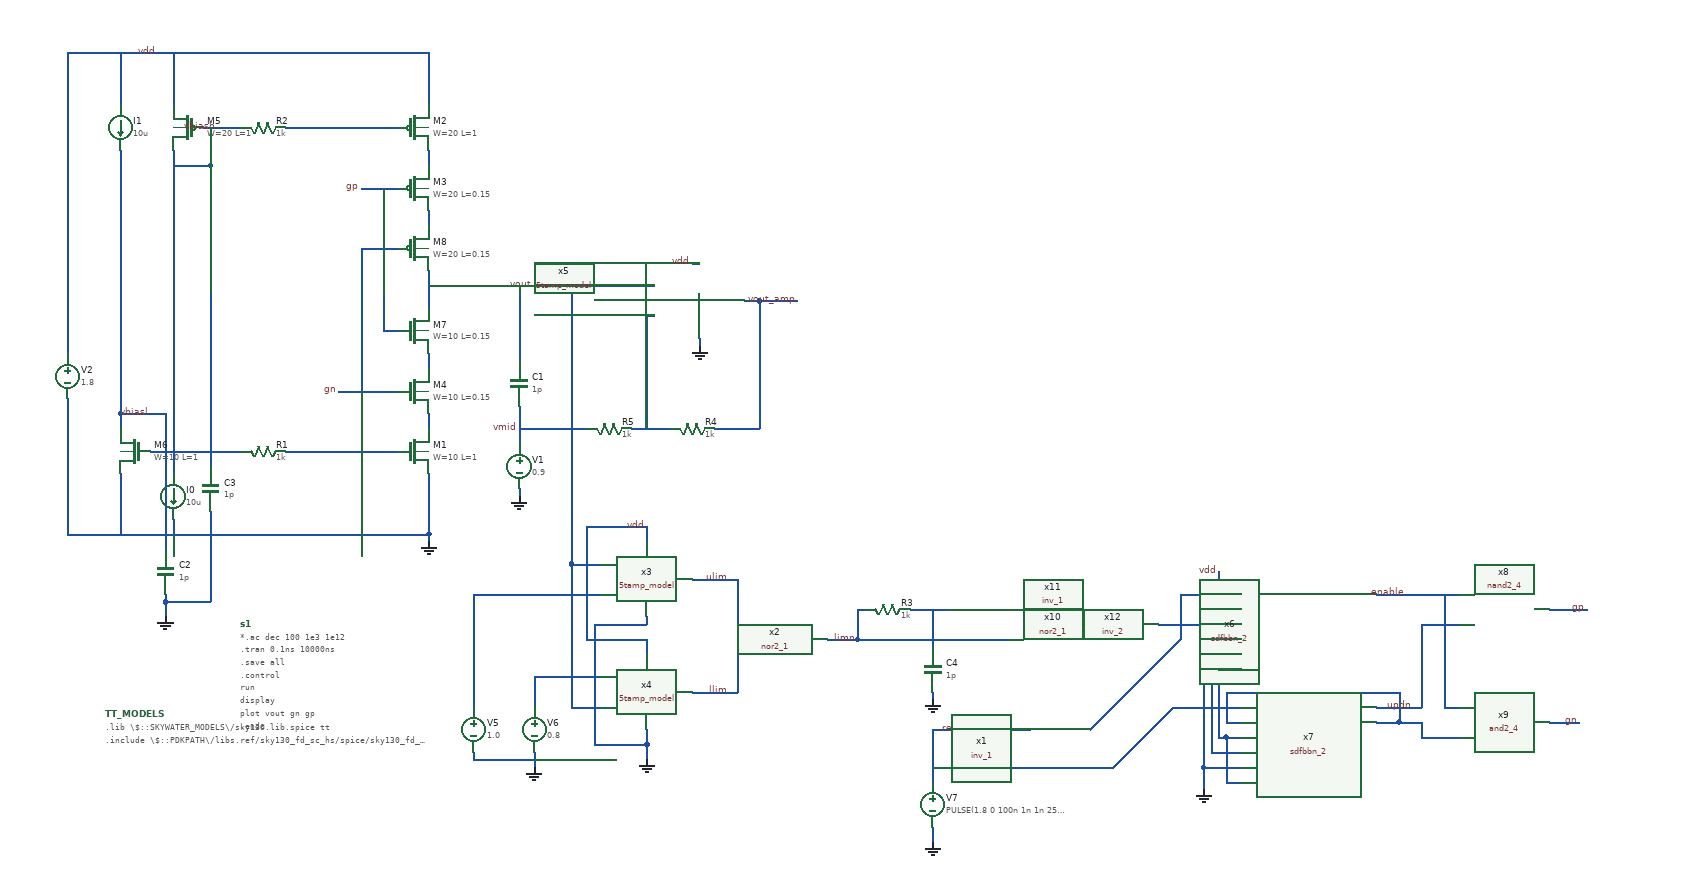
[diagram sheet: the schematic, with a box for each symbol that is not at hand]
v {xschem version=3.1.0 file_version=1.2
}
G {}
K {}
V {}
S {}
E {}
N 130 -490 170 -490 {
lab=#net1}
N 320 -590 320 -520 {
lab=vdd}
N 130 -60 170 -60 {
lab=#net2}
N 440 -200 440 -180 {
lab=vout}
N 440 -10 440 0 {
lab=GND}
N -160 -590 -20 -590 {
lab=vdd}
N -160 -130 -160 50 {
lab=GND}
N -20 -130 -20 -100 {
lab=vbiash}
N -20 -590 -20 -520 {
lab=vdd}
N -20 -100 -20 -30 {
lab=vbiash}
N -20 30 -20 50 {
lab=GND}
N -90 -30 -90 50 {
lab=GND}
N -30 -110 -30 -60 {
lab=vbiasl}
N -90 -110 -30 -110 {
lab=vbiasl}
N -90 -110 -90 -90 {
lab=vbiasl}
N -90 -130 -90 -110 {
lab=vbiasl}
N -90 -590 -90 -520 {
lab=vdd}
N -30 -60 -30 70 {
lab=vbiasl}
N 30 -100 30 -40 {
lab=vbiash}
N 30 20 30 140 {
lab=GND}
N -30 140 30 140 {
lab=GND}
N -30 130 -30 140 {
lab=GND}
N -30 140 -30 160 {
lab=GND}
N -20 -460 -20 -370 {
lab=vbiash}
N -90 -460 -90 -370 {
lab=vbiasl}
N -20 -440 30 -440 {
lab=vbiash}
N 30 -490 30 -440 {
lab=vbiash}
N 30 -200 30 -100 {
lab=vbiash}
N 320 -460 320 -440 {
lab=#net3}
N 320 -110 320 -90 {
lab=#net4}
N 440 -280 440 -200 {
lab=vout}
N 320 -30 320 50 {
lab=GND}
N 320 50 320 60 {
lab=GND}
N -160 -430 -160 -190 {
lab=vdd}
N -90 -210 -90 -130 {
lab=vbiasl}
N 320 -190 320 -170 {
lab=#net5}
N 320 -380 320 -360 {
lab=#net6}
N 320 -300 320 -250 {
lab=vout}
N 320 -280 390 -280 {
lab=vout}
N 30 -440 30 -200 {
lab=vbiash}
N -20 -370 -20 -130 {
lab=vbiash}
N -90 -370 -90 -210 {
lab=vbiasl}
N -160 -590 -160 -430 {
lab=vdd}
N 230 -330 230 -140 {
lab=gn}
N 230 -330 280 -330 {
lab=gn}
N 260 -410 260 -220 {
lab=gp}
N 260 -220 280 -220 {
lab=gp}
N 170 -490 280 -490 {
lab=#net1}
N 170 -60 280 -60 {
lab=#net2}
N -70 -590 320 -590 {
lab=vdd}
N 610 190 610 210 {
lab=vdd}
N 530 190 610 190 {
lab=vdd}
N 530 40 530 190 {
lab=vdd}
N 530 40 610 40 {
lab=vdd}
N 610 40 610 60 {
lab=vdd}
N 610 160 610 170 {
lab=GND}
N 540 170 610 170 {
lab=GND}
N 540 170 540 330 {
lab=GND}
N 540 330 610 330 {
lab=GND}
N 610 310 610 330 {
lab=GND}
N 610 330 610 350 {
lab=GND}
N 470 130 550 130 {
lab=#net7}
N 510 90 510 280 {
lab=vout}
N 510 280 550 280 {
lab=vout}
N 460 240 460 280 {
lab=#net8}
N 380 130 380 280 {
lab=#net7}
N 380 130 470 130 {
lab=#net7}
N 460 240 550 240 {
lab=#net8}
N 460 340 460 360 {
lab=GND}
N 380 340 380 350 {
lab=GND}
N 380 350 460 350 {
lab=GND}
N 730 110 730 170 {
lab=ulim}
N 720 110 730 110 {
lab=ulim}
N 730 210 730 260 {
lab=llim}
N 720 260 730 260 {
lab=llim}
N 1370 150 1390 150 {
lab=vdd}
N 990 440 990 460 {
lab=GND}
N 990 310 990 380 {
lab=refclk}
N 990 310 1120 310 {
lab=refclk}
N 1580 130 1630 130 {
lab=enable}
N 990 360 1120 360 {
lab=refclk}
N 1380 300 1400 300 {
lab=#net9}
N 1380 260 1380 300 {
lab=#net9}
N 1380 260 1610 260 {
lab=#net9}
N 1610 260 1610 300 {
lab=#net9}
N 1580 300 1610 300 {
lab=#net9}
N 1580 280 1640 280 {
lab=updn}
N 1380 320 1400 320 {
lab=vdd}
N 1380 320 1380 380 {
lab=vdd}
N 1380 380 1400 380 {
lab=vdd}
N 1390 150 1400 150 {
lab=vdd}
N 1370 150 1370 320 {
lab=vdd}
N 1370 320 1380 320 {
lab=vdd}
N 1630 130 1690 130 {
lab=enable}
N 1670 130 1670 280 {
lab=enable}
N 1670 280 1690 280 {
lab=enable}
N 1650 170 1690 170 {
lab=updn}
N 1640 170 1640 280 {
lab=updn}
N 1640 170 1650 170 {
lab=updn}
N 1610 300 1640 300 {
lab=#net9}
N 1640 300 1640 320 {
lab=#net9}
N 1640 320 1690 320 {
lab=#net9}
N 1810 150 1860 150 {
lab=gp}
N 1810 300 1850 300 {
lab=gn}
N 200 -140 280 -140 {
lab=gn}
N 230 -410 280 -410 {
lab=gp}
N 1360 340 1400 340 {
lab=#net10}
N 1360 190 1360 340 {
lab=#net10}
N 1360 190 1400 190 {
lab=#net10}
N 1350 210 1400 210 {
lab=GND}
N 1350 210 1350 360 {
lab=GND}
N 1350 360 1400 360 {
lab=GND}
N 1350 360 1350 390 {
lab=GND}
N 1340 130 1400 130 {
lab=#net11}
N 1370 100 1370 150 {
lab=vdd}
N 1370 230 1400 230 {
lab=vdd}
N 890 150 900 150 {
lab=limn}
N 960 150 1010 150 {
lab=#net12}
N 990 150 990 200 {
lab=#net12}
N 990 260 990 270 {
lab=GND}
N 890 190 1090 190 {
lab=limn}
N 890 150 890 190 {
lab=limn}
N 850 190 890 190 {
lab=limn}
N 670 110 720 110 {
lab=ulim}
N 670 260 720 260 {
lab=llim}
N 1310 280 1400 280 {
lab=refclk}
N 1290 170 1400 170 {
lab=#net13}
N 1320 130 1320 190 {
lab=#net11}
N 1320 130 1340 130 {
lab=#net11}
N 1200 310 1320 190 {
lab=#net11}
N 1120 360 1230 360 {
lab=refclk}
N 1230 360 1310 280 {
lab=refclk}
N -50 -60 70 -60 {
lab=vbiasl}
N 20 -490 70 -490 {
lab=vbiash}
N -160 50 320 50 {
lab=GND}
N 390 -280 460 -280 {
lab=vout}
N 510 90 550 90 {
lab=vout}
N 510 -280 510 90 {
lab=vout}
N 460 -280 510 -280 {
lab=vout}
N 670 -310 680 -310 {
lab=vdd}
N 440 -120 440 -70 {
lab=vmid}
N 680 -210 680 -200 {
lab=GND}
N 440 -90 530 -90 {
lab=vmid}
N 590 -90 640 -90 {
lab=#net14}
N 610 -240 620 -240 {
lab=#net14}
N 610 -240 610 -90 {
lab=#net14}
N 700 -90 760 -90 {
lab=vout_amp}
N 760 -260 760 -90 {
lab=vout_amp}
N 740 -260 760 -260 {
lab=vout_amp}
N 510 -280 620 -280 {
lab=vout}
N 760 -260 810 -260 {
lab=vout_amp}
C {sky130_fd_pr/nfet3_01v8.sym} 300 -60 0 0 {name=M1
L=1
W=10
body=GND
nf=1
mult=1
ad="'int((nf+1)/2) * W/nf * 0.29'" 
pd="'2*int((nf+1)/2) * (W/nf + 0.29)'"
as="'int((nf+2)/2) * W/nf * 0.29'" 
ps="'2*int((nf+2)/2) * (W/nf + 0.29)'"
nrd="'0.29 / W'" nrs="'0.29 / W'"
sa=0 sb=0 sd=0
model=nfet_01v8
spiceprefix=X
}
C {sky130_fd_pr/pfet3_01v8.sym} 300 -490 0 0 {name=M2
L=1
W=20
body=VDD
nf=1
mult=1
ad="'int((nf+1)/2) * W/nf * 0.29'" 
pd="'2*int((nf+1)/2) * (W/nf + 0.29)'"
as="'int((nf+2)/2) * W/nf * 0.29'" 
ps="'2*int((nf+2)/2) * (W/nf + 0.29)'"
nrd="'0.29 / W'" nrs="'0.29 / W'"
sa=0 sb=0 sd=0
model=pfet_01v8
spiceprefix=X
}
C {sky130_fd_pr/pfet3_01v8.sym} 300 -410 0 0 {name=M3
L=0.15
W=20
body=VDD
nf=1
mult=1
ad="'int((nf+1)/2) * W/nf * 0.29'" 
pd="'2*int((nf+1)/2) * (W/nf + 0.29)'"
as="'int((nf+2)/2) * W/nf * 0.29'" 
ps="'2*int((nf+2)/2) * (W/nf + 0.29)'"
nrd="'0.29 / W'" nrs="'0.29 / W'"
sa=0 sb=0 sd=0
model=pfet_01v8
spiceprefix=X
}
C {sky130_fd_pr/nfet3_01v8.sym} 300 -140 0 0 {name=M4
L=0.15
W=10
body=GND
nf=1
mult=1
ad="'int((nf+1)/2) * W/nf * 0.29'" 
pd="'2*int((nf+1)/2) * (W/nf + 0.29)'"
as="'int((nf+2)/2) * W/nf * 0.29'" 
ps="'2*int((nf+2)/2) * (W/nf + 0.29)'"
nrd="'0.29 / W'" nrs="'0.29 / W'"
sa=0 sb=0 sd=0
model=nfet_01v8
spiceprefix=X
}
C {devices/gnd.sym} 320 60 0 0 {name=l1 lab=GND}
C {devices/capa.sym} 440 -150 0 0 {name=C1
m=1
value=1p
footprint=1206
device="ceramic capacitor"}
C {devices/gnd.sym} 440 0 0 0 {name=l2 lab=GND}
C {devices/vsource.sym} 440 -40 0 0 {name=V1 value=0.9}
C {devices/vsource.sym} -160 -160 0 0 {name=V2 value=1.8}
C {sky130_fd_pr/pfet3_01v8.sym} 0 -490 0 1 {name=M5
L=1
W=20
body=VDD
nf=1
mult=1
ad="'int((nf+1)/2) * W/nf * 0.29'" 
pd="'2*int((nf+1)/2) * (W/nf + 0.29)'"
as="'int((nf+2)/2) * W/nf * 0.29'" 
ps="'2*int((nf+2)/2) * (W/nf + 0.29)'"
nrd="'0.29 / W'" nrs="'0.29 / W'"
sa=0 sb=0 sd=0
model=pfet_01v8
spiceprefix=X
}
C {devices/isource.sym} -20 0 0 0 {name=I0 value=10u}
C {sky130_fd_pr/nfet3_01v8.sym} -70 -60 0 1 {name=M6
L=1
W=10
body=GND
nf=1
mult=1
ad="'int((nf+1)/2) * W/nf * 0.29'" 
pd="'2*int((nf+1)/2) * (W/nf + 0.29)'"
as="'int((nf+2)/2) * W/nf * 0.29'" 
ps="'2*int((nf+2)/2) * (W/nf + 0.29)'"
nrd="'0.29 / W'" nrs="'0.29 / W'"
sa=0 sb=0 sd=0
model=nfet_01v8
spiceprefix=X
}
C {devices/isource.sym} -90 -490 0 0 {name=I1 value=10u}
C {devices/lab_wire.sym} -40 -590 0 0 {name=p1 sig_type=std_logic lab=vdd}
C {devices/lab_wire.sym} 460 -280 0 0 {name=p2 sig_type=std_logic lab=vout}
C {devices/lab_wire.sym} 200 -140 0 0 {name=p3 sig_type=std_logic lab=gn}
C {devices/code.sym} -110 290 0 0 {name=TT_MODELS only_toplevel=false
format="tcleval(@value )" value=".lib \\\\$::SKYWATER_MODELS\\\\/sky130.lib.spice tt
.include \\\\$::PDKPATH\\\\/libs.ref/sky130_fd_sc_hs/spice/sky130_fd_sc_hs.spice"}
C {devices/code_shown.sym} 70 170 0 0 {name=s1
only_toplevel=false
value="
*.ac dec 100 1e3 1e12
.tran 0.1ns 10000ns
.save all
.control
run
display
plot vout gn gp
.endc
"}
C {devices/lab_wire.sym} 230 -410 0 0 {name=p4 sig_type=std_logic lab=gp}
C {devices/lab_wire.sym} -50 -110 0 0 {name=p5 sig_type=std_logic lab=vbiasl}
C {devices/lab_wire.sym} 40 -490 0 0 {name=p6 sig_type=std_logic lab=vbiash}
C {devices/capa.sym} -30 100 0 0 {name=C2
m=1
value=1p
footprint=1206
device="ceramic capacitor"}
C {devices/capa.sym} 30 -10 0 0 {name=C3
m=1
value=1p
footprint=1206
device="ceramic capacitor"}
C {devices/gnd.sym} -30 160 0 0 {name=l6 lab=GND}
C {devices/res.sym} 100 -60 1 0 {name=R1
value=1k
footprint=1206
device=resistor
m=1}
C {devices/res.sym} 100 -490 1 0 {name=R2
value=1k
footprint=1206
device=resistor
m=1}
C {sky130_fd_pr/nfet3_01v8.sym} 300 -220 0 0 {name=M7
L=0.15
W=10
body=GND
nf=1
mult=1
ad="'int((nf+1)/2) * W/nf * 0.29'" 
pd="'2*int((nf+1)/2) * (W/nf + 0.29)'"
as="'int((nf+2)/2) * W/nf * 0.29'" 
ps="'2*int((nf+2)/2) * (W/nf + 0.29)'"
nrd="'0.29 / W'" nrs="'0.29 / W'"
sa=0 sb=0 sd=0
model=nfet_01v8
spiceprefix=X
}
C {sky130_fd_pr/pfet3_01v8.sym} 300 -330 0 0 {name=M8
L=0.15
W=20
body=VDD
nf=1
mult=1
ad="'int((nf+1)/2) * W/nf * 0.29'" 
pd="'2*int((nf+1)/2) * (W/nf + 0.29)'"
as="'int((nf+2)/2) * W/nf * 0.29'" 
ps="'2*int((nf+2)/2) * (W/nf + 0.29)'"
nrd="'0.29 / W'" nrs="'0.29 / W'"
sa=0 sb=0 sd=0
model=pfet_01v8
spiceprefix=X
}
C {5tamp_model.sym} 610 110 0 0 {name=x3}
C {5tamp_model.sym} 610 260 0 0 {name=x4}
C {devices/lab_wire.sym} 610 40 0 0 {name=p7 sig_type=std_logic lab=vdd}
C {devices/gnd.sym} 610 350 0 0 {name=l5 lab=GND}
C {devices/lab_wire.sym} 720 110 0 0 {name=p8 sig_type=std_logic lab=ulim}
C {devices/lab_wire.sym} 720 260 0 0 {name=p9 sig_type=std_logic lab=llim}
C {devices/vsource.sym} 380 310 0 0 {name=V5 value="1.0"}
C {devices/vsource.sym} 460 310 0 0 {name=V6 value="0.8"}
C {devices/gnd.sym} 460 360 0 0 {name=l7 lab=GND}
C {sky130_stdcells/sdfbbn_2.sym} 1490 180 0 0 {name=x6 VGND=gnd VNB=gnd VPB=vdd VPWR=vdd prefix=sky130_fd_sc_hs__ 
}
C {devices/lab_wire.sym} 1370 100 0 0 {name=p11 sig_type=std_logic lab=vdd}
C {devices/vsource.sym} 990 410 0 0 {name=V7 value="PULSE(1.8 0 100n 1n 1n 250n 500n)"}
C {devices/gnd.sym} 990 460 0 0 {name=l8 lab=GND}
C {devices/lab_wire.sym} 1040 310 0 0 {name=p12 sig_type=std_logic lab=refclk}
C {devices/lab_wire.sym} 1620 130 0 0 {name=p13 sig_type=std_logic lab=enable}
C {sky130_stdcells/sdfbbn_2.sym} 1490 330 0 0 {name=x7 VGND=gnd VNB=gnd VPB=vdd VPWR=vdd prefix=sky130_fd_sc_hs__ 
}
C {devices/lab_wire.sym} 1630 280 0 0 {name=p15 sig_type=std_logic lab=updn}
C {sky130_stdcells/nand2_4.sym} 1750 150 0 0 {name=x8 VGND=gnd VNB=gnd VPB=vdd VPWR=vdd prefix=sky130_fd_sc_hs__ }
C {sky130_stdcells/and2_4.sym} 1750 300 0 0 {name=x9 VGND=gnd VNB=gnd VPB=vdd VPWR=vdd prefix=sky130_fd_sc_hs__ 
}
C {devices/lab_wire.sym} 1860 150 0 0 {name=p16 sig_type=std_logic lab=gp}
C {devices/lab_wire.sym} 1850 300 0 0 {name=p17 sig_type=std_logic lab=gn}
C {devices/gnd.sym} 1350 390 0 0 {name=l9 lab=GND}
C {devices/lab_wire.sym} 890 190 0 0 {name=p14 sig_type=std_logic lab=limn}
C {devices/res.sym} 930 150 1 0 {name=R3
value=1k
footprint=1206
device=resistor
m=1}
C {devices/capa.sym} 990 230 0 0 {name=C4
m=1
value=1p
footprint=1206
device="ceramic capacitor"}
C {devices/gnd.sym} 990 270 0 0 {name=l3 lab=GND}
C {sky130_stdcells/inv_1.sym} 1050 150 0 0 {name=x11 VGND=gnd VNB=gnd VPB=vdd VPWR=vdd prefix=sky130_fd_sc_hs__ 
}
C {sky130_stdcells/inv_1.sym} 1160 310 0 0 {name=x1 VGND=gnd VNB=gnd VPB=vdd VPWR=vdd prefix=sky130_fd_sc_hs__ 
}
C {sky130_stdcells/nor2_1.sym} 790 190 0 0 {name=x2 VGND=gnd VNB=gnd VPB=vdd VPWR=vdd prefix=sky130_fd_sc_hs__ 
}
C {sky130_stdcells/nor2_1.sym} 1150 170 0 0 {name=x10 VGND=gnd VNB=gnd VPB=vdd VPWR=vdd prefix=sky130_fd_sc_hs__ 
}
C {sky130_stdcells/inv_2.sym} 1250 170 0 0 {name=x12 VGND=gnd VNB=gnd VPB=vdd VPWR=vdd prefix=sky130_fd_sc_hs__ 
}
C {5tamp_model.sym} 680 -260 0 0 {name=x5}
C {devices/lab_wire.sym} 670 -310 0 0 {name=p10 sig_type=std_logic lab=vdd}
C {devices/gnd.sym} 680 -200 0 0 {name=l4 lab=GND}
C {devices/lab_wire.sym} 440 -90 0 0 {name=p18 sig_type=std_logic lab=vmid}
C {devices/res.sym} 670 -90 1 0 {name=R4
value=1k
footprint=1206
device=resistor
m=1}
C {devices/res.sym} 560 -90 1 0 {name=R5
value=1k
footprint=1206
device=resistor
m=1}
C {devices/lab_wire.sym} 810 -260 0 0 {name=p19 sig_type=std_logic lab=vout_amp}
